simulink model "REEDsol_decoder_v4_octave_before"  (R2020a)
settings: Solver=VariableStepAuto  StartTime=0.0  StopTime=700  RelTol=1e-3
InitFcn:
  | FrameSize = 32+1784+256+32;
  | SamplingTime = 1/(38.4e3)*2;
  | IQframeSize = (32+1784+256+32)/2;
  | %同期コードが必ず含まれるように32を足す
  | h_time = 1;
  | 
  | % General simulation parameters
  | M = 4;                         % M-PSK alphabet size
  | Upsampling = 4;            % Upsampling factor
  | Downsampling = 2;        % Downsampling factor
  | Fs = 2e6;                     % Sample rate
  | Ts = 1/Fs;                    % Sample time
  | %%FrameSize = 111;          % Number of modulated symbols per frame
  | %MessageLength = 105;  % Number of message bits per frame, 7 ASCII characters
  | BarkerLength = 13;        % Number of Barker code symbols
  | 
  | % TED
  | %fs = 2.4e6;
  | %fs = Fs/2;
  | fs = Fs;
  | Rdata = 100e3;
  | Rsymbol = Rdata/2;
  | 
  | % --- Early Late Timing Synchronisation ----
  | % synch loop design
  | d = 0.707;                   % damping ratio
  | 
  | %Ts = 1/Rsymbol;           % symbol period
  | Ks = 3.22;                    % phase detector coefficient
  | BnS = 0.1*Rsymbol;      % noise bandwidth in Hz
  | Kn   = 1;                      % gain of numerically controlled clock
  | 
  | % calculate loop filter coefficients
  | Ka = (4*d*BnS*Ts)/(Kn*Ks*(d+1/(4*d)));
  | Kb = (4*(BnS*Ts)^2)/(Kn*Ks*(d+1/4*d)^2);
undefined symbols (not defined in the file or in its folder): Column, D, vector
libraries: commutil2 x2, dspindex x1

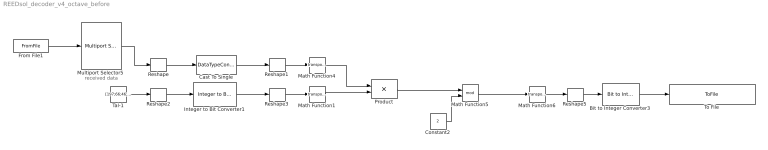
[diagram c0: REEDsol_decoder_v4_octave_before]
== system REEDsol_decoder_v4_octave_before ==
  note: received data
  Bit to Integer Converter3 : commutil2/Bit to Integer Converter  nbits=8  bitOrder=MSB first  signedOutputValues=Unsigned  outDtype=double  outDtypeSigned=int32
  Cast To Single : DataTypeConversion  OutDataTypeStr=single
  Constant2 : Constant  Value=2  VectorParams1D=off  OutDataTypeStr=single
  From File1 : FromFile  FileName=C:\Users\Eve\Desktop\sample_code_Simulink\data_analysis\QPSK_decodedata_20210118_4th_v.mat  SampleTime=0.05395833  ExtrapolationBeforeFirstDataPoint=Ground value  InterpolationWithinTimeRange=Zero order hold  ExtrapolationAfterLastDataPoint=Ground value
  Integer to Bit Converter1 : commutil2/Integer to Bit Converter  nbits=8  signedInputValues=Unsigned  bitOrder=MSB first  outDtype=single
  Math Function1 : Math  Operator=transpose  SignedPower=on
  Math Function4 : Math  Operator=transpose  SignedPower=on  OutputSignalType=real
  Math Function5 : Math  Operator=mod  SignedPower=on
  Math Function6 : Math  Operator=transpose  SignedPower=on
  Multiport Selector5 : dspindex/Multiport Selector  rowsOrCols=Rows  idxCellArray=[33:2072]  idxErrMode=Clip Index
  Product : Product  Multiplication=Matrix(*)
  Reshape : Reshape  OutputDimensionality=Column vector (2-D)
  Reshape1 : Reshape  OutputDimensionality=Customize  OutputDimensions=[8,255]
  Reshape2 : Reshape  OutputDimensionality=Column vector (2-D)  OutputDimensions=[1,8]
  Reshape3 : Reshape  OutputDimensionality=Customize  OutputDimensions=[8,8]
  Reshape5 : Reshape  OutputDimensionality=Column vector (2-D)
  Tal-1 : Constant  Value=[197;66;46;253;240;121;172;204]  VectorParams1D=off  OutDataTypeStr=single
  To File : ToFile  Filename=C:\Users\Eve\Desktop\sample_code_Simulink\data_analysisoctave_input.mat  MatrixName=ans_decode
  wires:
  Reshape1/1 -> Math Function4/1
  Math Function4/1 -> Product/1
  Reshape3/1 -> Math Function1/1
  Integer to Bit Converter1/1 -> Reshape3/1
  Reshape2/1 -> Integer to Bit Converter1/1
  Math Function1/1 -> Product/2
  Constant2/1 -> Math Function5/2
  Math Function5/1 -> Math Function6/1
  Product/1 -> Math Function5/1
  Math Function6/1 -> Reshape5/1
  Reshape5/1 -> Bit to Integer Converter3/1
  Tal-1/1 -> Reshape2/1
  Bit to Integer Converter3/1 -> To File/1
  Reshape/1 -> Cast To Single/1
  Cast To Single/1 -> Reshape1/1
  From File1/1 -> Multiport Selector5/1
  Multiport Selector5/1 -> Reshape/1
